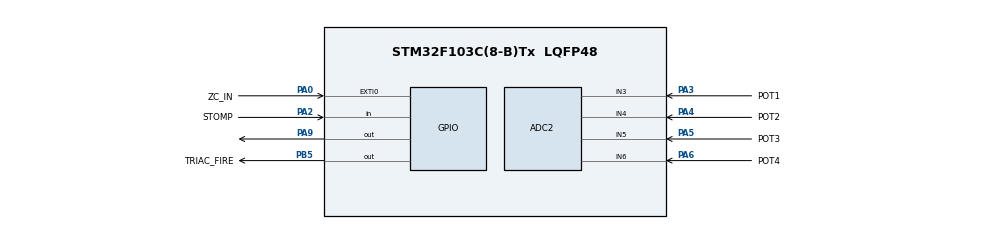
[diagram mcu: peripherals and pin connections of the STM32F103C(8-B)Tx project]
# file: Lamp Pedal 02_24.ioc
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ADC2.Channel-0\#ChannelRegularConversion=ADC_CHANNEL_3
ADC2.NbrOfConversionFlag=1
ADC2.Rank-0\#ChannelRegularConversion=1
ADC2.SamplingTime-0\#ChannelRegularConversion=ADC_SAMPLETIME_1CYCLE_5
Mcu.Family=STM32F1
Mcu.Name=STM32F103C(8-B)Tx
Mcu.Package=LQFP48
NVIC.EXTI0_IRQn=true\:0\:0\:false\:false\:true\:true\:true\:true
NVIC.PriorityGroup=NVIC_PRIORITYGROUP_4
NVIC.TIM2_IRQn=true\:1\:0\:true\:false\:true\:true\:true\:true
PA0-WKUP.GPIO_Label=ZC_IN
PA0-WKUP.GPIO_ModeDefaultEXTI=GPIO_MODE_IT_FALLING
PA0-WKUP.Signal=GPXTI0
PA13.Mode=Serial_Wire
PA13.Signal=SYS_JTMS-SWDIO
PA14.Mode=Serial_Wire
PA14.Signal=SYS_JTCK-SWCLK
PA2.GPIO_Label=STOMP
PA2.Signal=GPIO_Input
PA3.GPIO_Label=POT1
PA3.Signal=ADCx_IN3
PA4.GPIO_Label=POT2
PA4.Signal=ADCx_IN4
PA5.GPIO_Label=POT3
PA5.Signal=ADCx_IN5
PA6.GPIO_Label=POT4
PA6.Signal=ADCx_IN6
PA9.Signal=GPIO_Output
PB5.GPIO_Label=TRIAC_FIRE
PB5.Signal=GPIO_Output
PD0-OSC_IN.Mode=HSE-External-Oscillator
PD0-OSC_IN.Signal=RCC_OSC_IN
PD1-OSC_OUT.Mode=HSE-External-Oscillator
PD1-OSC_OUT.Signal=RCC_OSC_OUT
ProjectManager.HeapSize=0x200
ProjectManager.StackSize=0x400
ProjectManager.TargetToolchain=STM32CubeIDE
RCC.AHBFreq_Value=16000000
RCC.APB1Freq_Value=16000000
RCC.APB1TimFreq_Value=16000000
RCC.APB2Freq_Value=16000000
RCC.APB2TimFreq_Value=16000000
RCC.HCLKFreq_Value=16000000
RCC.PLLSourceVirtual=RCC_PLLSOURCE_HSE
RCC.SYSCLKFreq_VALUE=16000000
RCC.SYSCLKSource=RCC_SYSCLKSOURCE_PLLCLK
RCC.USBFreq_Value=16000000
SH.ADCx_IN3.0=ADC2_IN3,IN3
SH.ADCx_IN4.0=ADC2_IN4,IN4
SH.ADCx_IN5.0=ADC2_IN5,IN5
SH.ADCx_IN6.0=ADC2_IN6,IN6
TIM1.Prescaler=16-1
TIM2.AutoReloadPreload=TIM_AUTORELOAD_PRELOAD_DISABLE
TIM2.Period=8333-1
TIM2.Prescaler=16-1
TIM4.Prescaler=1600-1
VP_TIM1_VS_ClockSourceINT.Mode=Internal
VP_TIM2_VS_ClockSourceINT.Mode=Internal
VP_TIM4_VS_ClockSourceITR.Mode=TriggerSource_ITR1
board=custom

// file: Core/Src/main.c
/* USER CODE BEGIN Header */
/**
  ******************************************************************************
  * @file           : main.c
  * @brief          : Main program body
  ******************************************************************************
  * @attention
  *
  * <h2><center>&copy; Copyright (c) 2024 STMicroelectronics.
  * All rights reserved.</center></h2>
  *
  * This software component is licensed by ST under BSD 3-Clause license,
  * the "License"; You may not use this file except in compliance with the
  * License. You may obtain a copy of the License at:
  *                        opensource.org/licenses/BSD-3-Clause
  *.
  ******************************************************************************
  */
/* USER CODE END Header */
#include "main.h"

/* USER CODE BEGIN Includes */

#include "../../Drivers/delay_us.h"

/* USER CODE END Includes */

ADC_HandleTypeDef hadc2;

TIM_HandleTypeDef htim1;
TIM_HandleTypeDef htim2;
TIM_HandleTypeDef htim4;

void SystemClock_Config(void);
static void MX_GPIO_Init(void);
static void MX_ADC2_Init(void);
static void MX_TIM1_Init(void);
static void MX_TIM4_Init(void);
static void MX_TIM2_Init(void);
/* USER CODE BEGIN PFP */

int adcval_to_us(int);

/* USER CODE END PFP */

/* USER CODE BEGIN 0 */

uint16_t triac_fire_delay_us;
uint16_t num_zero_crossings = 0;

/* USER CODE END 0 */

int main(void)
{
  /* USER CODE BEGIN 1 */
	uint16_t pot1_adc_retval;
	//char msg[10];
  /* USER CODE END 1 */

  /* MCU Configuration--------------------------------------------------------*/

  /* Reset of all peripherals, Initializes the Flash interface and the Systick. */
  HAL_Init();

  /* Configure the system clock */
  SystemClock_Config();

  /* Initialize all configured peripherals */
  MX_GPIO_Init();
  MX_ADC2_Init();
  MX_TIM1_Init();
  MX_TIM4_Init();
  MX_TIM2_Init();
  /* USER CODE BEGIN 2 */

  // Start timers
  HAL_TIM_Base_Start(&htim1);
  HAL_TIM_Base_Start(&htim4);

  // Get timer 4 value (used for debug)
  uint16_t timer4_val = __HAL_TIM_GET_COUNTER(&htim4);

  /* USER CODE END 2 */

  /* Infinite loop */
  /* USER CODE BEGIN WHILE */
  while (1)
  {
	// Get POT1 value with adc2
	HAL_ADC_Start(&hadc2);
	HAL_ADC_PollForConversion(&hadc2, HAL_MAX_DELAY);
	pot1_adc_retval = HAL_ADC_GetValue(&hadc2);

	// Convert raw POT1 ADC value (max 4096) to triac fire delay in microseconds
	// Max value for triac fire delay is 8333 microseconds, or half 60Hz sine period
	triac_fire_delay_us = adcval_to_us(pot1_adc_retval);

	// Opportunity to check how many zero crossings have occurred with a breakpoint. num_zero_crossings resets every second.
	if (__HAL_TIM_GET_COUNTER(&htim4) - timer4_val >= 10000)
	{
		num_zero_crossings = 0;
		timer4_val = __HAL_TIM_GET_COUNTER(&htim4);
	}

    /* USER CODE END WHILE */

  }
}

void SystemClock_Config(void)
{
  RCC_OscInitTypeDef RCC_OscInitStruct = {0};
  RCC_ClkInitTypeDef RCC_ClkInitStruct = {0};
  RCC_PeriphCLKInitTypeDef PeriphClkInit = {0};

  /** Initializes the RCC Oscillators according to the specified parameters
  * in the RCC_OscInitTypeDef structure.
  */
  RCC_OscInitStruct.OscillatorType = RCC_OSCILLATORTYPE_HSE;
  RCC_OscInitStruct.HSEState = RCC_HSE_ON;
  RCC_OscInitStruct.HSEPredivValue = RCC_HSE_PREDIV_DIV1;
  RCC_OscInitStruct.HSIState = RCC_HSI_ON;
  RCC_OscInitStruct.PLL.PLLState = RCC_PLL_ON;
  RCC_OscInitStruct.PLL.PLLSource = RCC_PLLSOURCE_HSE;
  RCC_OscInitStruct.PLL.PLLMUL = RCC_PLL_MUL2;
  if (HAL_RCC_OscConfig(&RCC_OscInitStruct) != HAL_OK)
  {
    Error_Handler();
  }
  /** Initializes the CPU, AHB and APB buses clocks
  */
  RCC_ClkInitStruct.ClockType = RCC_CLOCKTYPE_HCLK|RCC_CLOCKTYPE_SYSCLK
                              |RCC_CLOCKTYPE_PCLK1|RCC_CLOCKTYPE_PCLK2;
  RCC_ClkInitStruct.SYSCLKSource = RCC_SYSCLKSOURCE_PLLCLK;
  RCC_ClkInitStruct.AHBCLKDivider = RCC_SYSCLK_DIV1;
  RCC_ClkInitStruct.APB1CLKDivider = RCC_HCLK_DIV2;
  RCC_ClkInitStruct.APB2CLKDivider = RCC_HCLK_DIV1;

  if (HAL_RCC_ClockConfig(&RCC_ClkInitStruct, FLASH_LATENCY_0) != HAL_OK)
  {
    Error_Handler();
  }
  PeriphClkInit.PeriphClockSelection = RCC_PERIPHCLK_ADC;
  PeriphClkInit.AdcClockSelection = RCC_ADCPCLK2_DIV2;
  if (HAL_RCCEx_PeriphCLKConfig(&PeriphClkInit) != HAL_OK)
  {
    Error_Handler();
  }
}

static void MX_ADC2_Init(void)
{

  ADC_ChannelConfTypeDef sConfig = {0};

  /** Common config
  */
  hadc2.Instance = ADC2;
  hadc2.Init.ScanConvMode = ADC_SCAN_DISABLE;
  hadc2.Init.ContinuousConvMode = DISABLE;
  hadc2.Init.DiscontinuousConvMode = DISABLE;
  hadc2.Init.ExternalTrigConv = ADC_SOFTWARE_START;
  hadc2.Init.DataAlign = ADC_DATAALIGN_RIGHT;
  hadc2.Init.NbrOfConversion = 1;
  if (HAL_ADC_Init(&hadc2) != HAL_OK)
  {
    Error_Handler();
  }
  /** Configure Regular Channel
  */
  sConfig.Channel = ADC_CHANNEL_3;
  sConfig.Rank = ADC_REGULAR_RANK_1;
  sConfig.SamplingTime = ADC_SAMPLETIME_1CYCLE_5;
  if (HAL_ADC_ConfigChannel(&hadc2, &sConfig) != HAL_OK)
  {
    Error_Handler();
  }

}

static void MX_TIM1_Init(void)
{

  TIM_ClockConfigTypeDef sClockSourceConfig = {0};
  TIM_MasterConfigTypeDef sMasterConfig = {0};

  htim1.Instance = TIM1;
  htim1.Init.Prescaler = 16-1;
  htim1.Init.CounterMode = TIM_COUNTERMODE_UP;
  htim1.Init.Period = 65535;
  htim1.Init.ClockDivision = TIM_CLOCKDIVISION_DIV1;
  htim1.Init.RepetitionCounter = 0;
  htim1.Init.AutoReloadPreload = TIM_AUTORELOAD_PRELOAD_DISABLE;
  if (HAL_TIM_Base_Init(&htim1) != HAL_OK)
  {
    Error_Handler();
  }
  sClockSourceConfig.ClockSource = TIM_CLOCKSOURCE_INTERNAL;
  if (HAL_TIM_ConfigClockSource(&htim1, &sClockSourceConfig) != HAL_OK)
  {
    Error_Handler();
  }
  sMasterConfig.MasterOutputTrigger = TIM_TRGO_RESET;
  sMasterConfig.MasterSlaveMode = TIM_MASTERSLAVEMODE_DISABLE;
  if (HAL_TIMEx_MasterConfigSynchronization(&htim1, &sMasterConfig) != HAL_OK)
  {
    Error_Handler();
  }

}

static void MX_TIM2_Init(void)
{

  TIM_ClockConfigTypeDef sClockSourceConfig = {0};
  TIM_SlaveConfigTypeDef sSlaveConfig = {0};
  TIM_MasterConfigTypeDef sMasterConfig = {0};

  htim2.Instance = TIM2;
  htim2.Init.Prescaler = 16 - 1;
  htim2.Init.CounterMode = TIM_COUNTERMODE_UP;
  htim2.Init.Period = 8333/2 - 1;
  htim2.Init.ClockDivision = TIM_CLOCKDIVISION_DIV1;
  htim2.Init.AutoReloadPreload = TIM_AUTORELOAD_PRELOAD_DISABLE;
  if (HAL_TIM_Base_Init(&htim2) != HAL_OK)
  {
    Error_Handler();
  }
  sClockSourceConfig.ClockSource = TIM_CLOCKSOURCE_ETRMODE2;
  sClockSourceConfig.ClockPolarity = TIM_CLOCKPOLARITY_NONINVERTED;
  sClockSourceConfig.ClockPrescaler = TIM_CLOCKPRESCALER_DIV1;
  sClockSourceConfig.ClockFilter = 0;
  if (HAL_TIM_ConfigClockSource(&htim2, &sClockSourceConfig) != HAL_OK)
  {
    Error_Handler();
  }
  sSlaveConfig.SlaveMode = TIM_SLAVEMODE_RESET;
  sSlaveConfig.InputTrigger = TIM_TS_ITR0;
  if (HAL_TIM_SlaveConfigSynchro(&htim2, &sSlaveConfig) != HAL_OK)
  {
    Error_Handler();
  }
  sMasterConfig.MasterOutputTrigger = TIM_TRGO_RESET;
  sMasterConfig.MasterSlaveMode = TIM_MASTERSLAVEMODE_DISABLE;
  if (HAL_TIMEx_MasterConfigSynchronization(&htim2, &sMasterConfig) != HAL_OK)
  {
    Error_Handler();
  }

}

static void MX_TIM4_Init(void)
{

  TIM_SlaveConfigTypeDef sSlaveConfig = {0};
  TIM_MasterConfigTypeDef sMasterConfig = {0};

  htim4.Instance = TIM4;
  htim4.Init.Prescaler = 1600-1;
  htim4.Init.CounterMode = TIM_COUNTERMODE_UP;
  htim4.Init.Period = 65535;
  htim4.Init.ClockDivision = TIM_CLOCKDIVISION_DIV1;
  htim4.Init.AutoReloadPreload = TIM_AUTORELOAD_PRELOAD_DISABLE;
  if (HAL_TIM_Base_Init(&htim4) != HAL_OK)
  {
    Error_Handler();
  }
  sSlaveConfig.SlaveMode = TIM_SLAVEMODE_DISABLE;
  sSlaveConfig.InputTrigger = TIM_TS_ITR1;
  if (HAL_TIM_SlaveConfigSynchro(&htim4, &sSlaveConfig) != HAL_OK)
  {
    Error_Handler();
  }
  sMasterConfig.MasterOutputTrigger = TIM_TRGO_RESET;
  sMasterConfig.MasterSlaveMode = TIM_MASTERSLAVEMODE_DISABLE;
  if (HAL_TIMEx_MasterConfigSynchronization(&htim4, &sMasterConfig) != HAL_OK)
  {
    Error_Handler();
  }

}

static void MX_GPIO_Init(void)
{
  GPIO_InitTypeDef GPIO_InitStruct = {0};

  /* GPIO Ports Clock Enable */
  __HAL_RCC_GPIOD_CLK_ENABLE();
  __HAL_RCC_GPIOA_CLK_ENABLE();
  __HAL_RCC_GPIOB_CLK_ENABLE();

  /*Configure GPIO pin Output Level */
  HAL_GPIO_WritePin(GPIOA, GPIO_PIN_9, GPIO_PIN_RESET);

  /*Configure GPIO pin Output Level */
  HAL_GPIO_WritePin(TRIAC_FIRE_GPIO_Port, TRIAC_FIRE_Pin, GPIO_PIN_RESET);

  /*Configure GPIO pin : STOMP_Pin */
  GPIO_InitStruct.Pin = STOMP_Pin;
  GPIO_InitStruct.Mode = GPIO_MODE_INPUT;
  GPIO_InitStruct.Pull = GPIO_NOPULL;
  HAL_GPIO_Init(STOMP_GPIO_Port, &GPIO_InitStruct);

  /*Configure GPIO pin : PA9 */
  GPIO_InitStruct.Pin = GPIO_PIN_9;
  GPIO_InitStruct.Mode = GPIO_MODE_OUTPUT_PP;
  GPIO_InitStruct.Pull = GPIO_NOPULL;
  GPIO_InitStruct.Speed = GPIO_SPEED_FREQ_LOW;
  HAL_GPIO_Init(GPIOA, &GPIO_InitStruct);

  /*Configure GPIO pin : TRIAC_FIRE_Pin */
  GPIO_InitStruct.Pin = TRIAC_FIRE_Pin;
  GPIO_InitStruct.Mode = GPIO_MODE_OUTPUT_PP;
  GPIO_InitStruct.Pull = GPIO_NOPULL;
  GPIO_InitStruct.Speed = GPIO_SPEED_FREQ_LOW;
  HAL_GPIO_Init(TRIAC_FIRE_GPIO_Port, &GPIO_InitStruct);

}

/* USER CODE BEGIN 4 */

// EXTI Line0 External Interrupt ISR Handler CallBackFun
void HAL_GPIO_EXTI_Callback(uint16_t GPIO_Pin)
{
    if(GPIO_Pin == ZC_IN_Pin) // If The INT Source Is EXTI Line0 (A0 Pin)
    {
    	num_zero_crossings++;
    	HAL_GPIO_WritePin(GPIOB, TRIAC_FIRE_Pin, GPIO_PIN_SET); // Reset triac
    	delay_us(triac_fire_delay_us, &htim1);
    	HAL_GPIO_WritePin(GPIOB, TRIAC_FIRE_Pin, GPIO_PIN_RESET); // Fire triac
    }
}

int adcval_to_us(int rawADCValue)
{
	const int max_adcval = 4096;
	const int max_us = 8333;

	// Ensure input is within valid range
	if (max_adcval < 0)
	{
		rawADCValue = 0;
	}
	else if (rawADCValue > max_adcval)
	{
		rawADCValue = max_adcval;
	}

	// Perform linear scaling
	return (rawADCValue * max_us) / max_adcval;
}

/* USER CODE END 4 */

void Error_Handler(void)
{
  __disable_irq();
  while (1)
  {
  }
}

/************************ (C) COPYRIGHT STMicroelectronics *****END OF FILE****/
